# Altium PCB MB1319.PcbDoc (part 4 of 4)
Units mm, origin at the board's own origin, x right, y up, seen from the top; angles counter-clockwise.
Board outline 70 x 82.5 mm, 2 copper layers (Top Layer, Bottom Layer), stack 1.571 mm thick; 252 components, 179 nets, 814 pads, 1000 vias.

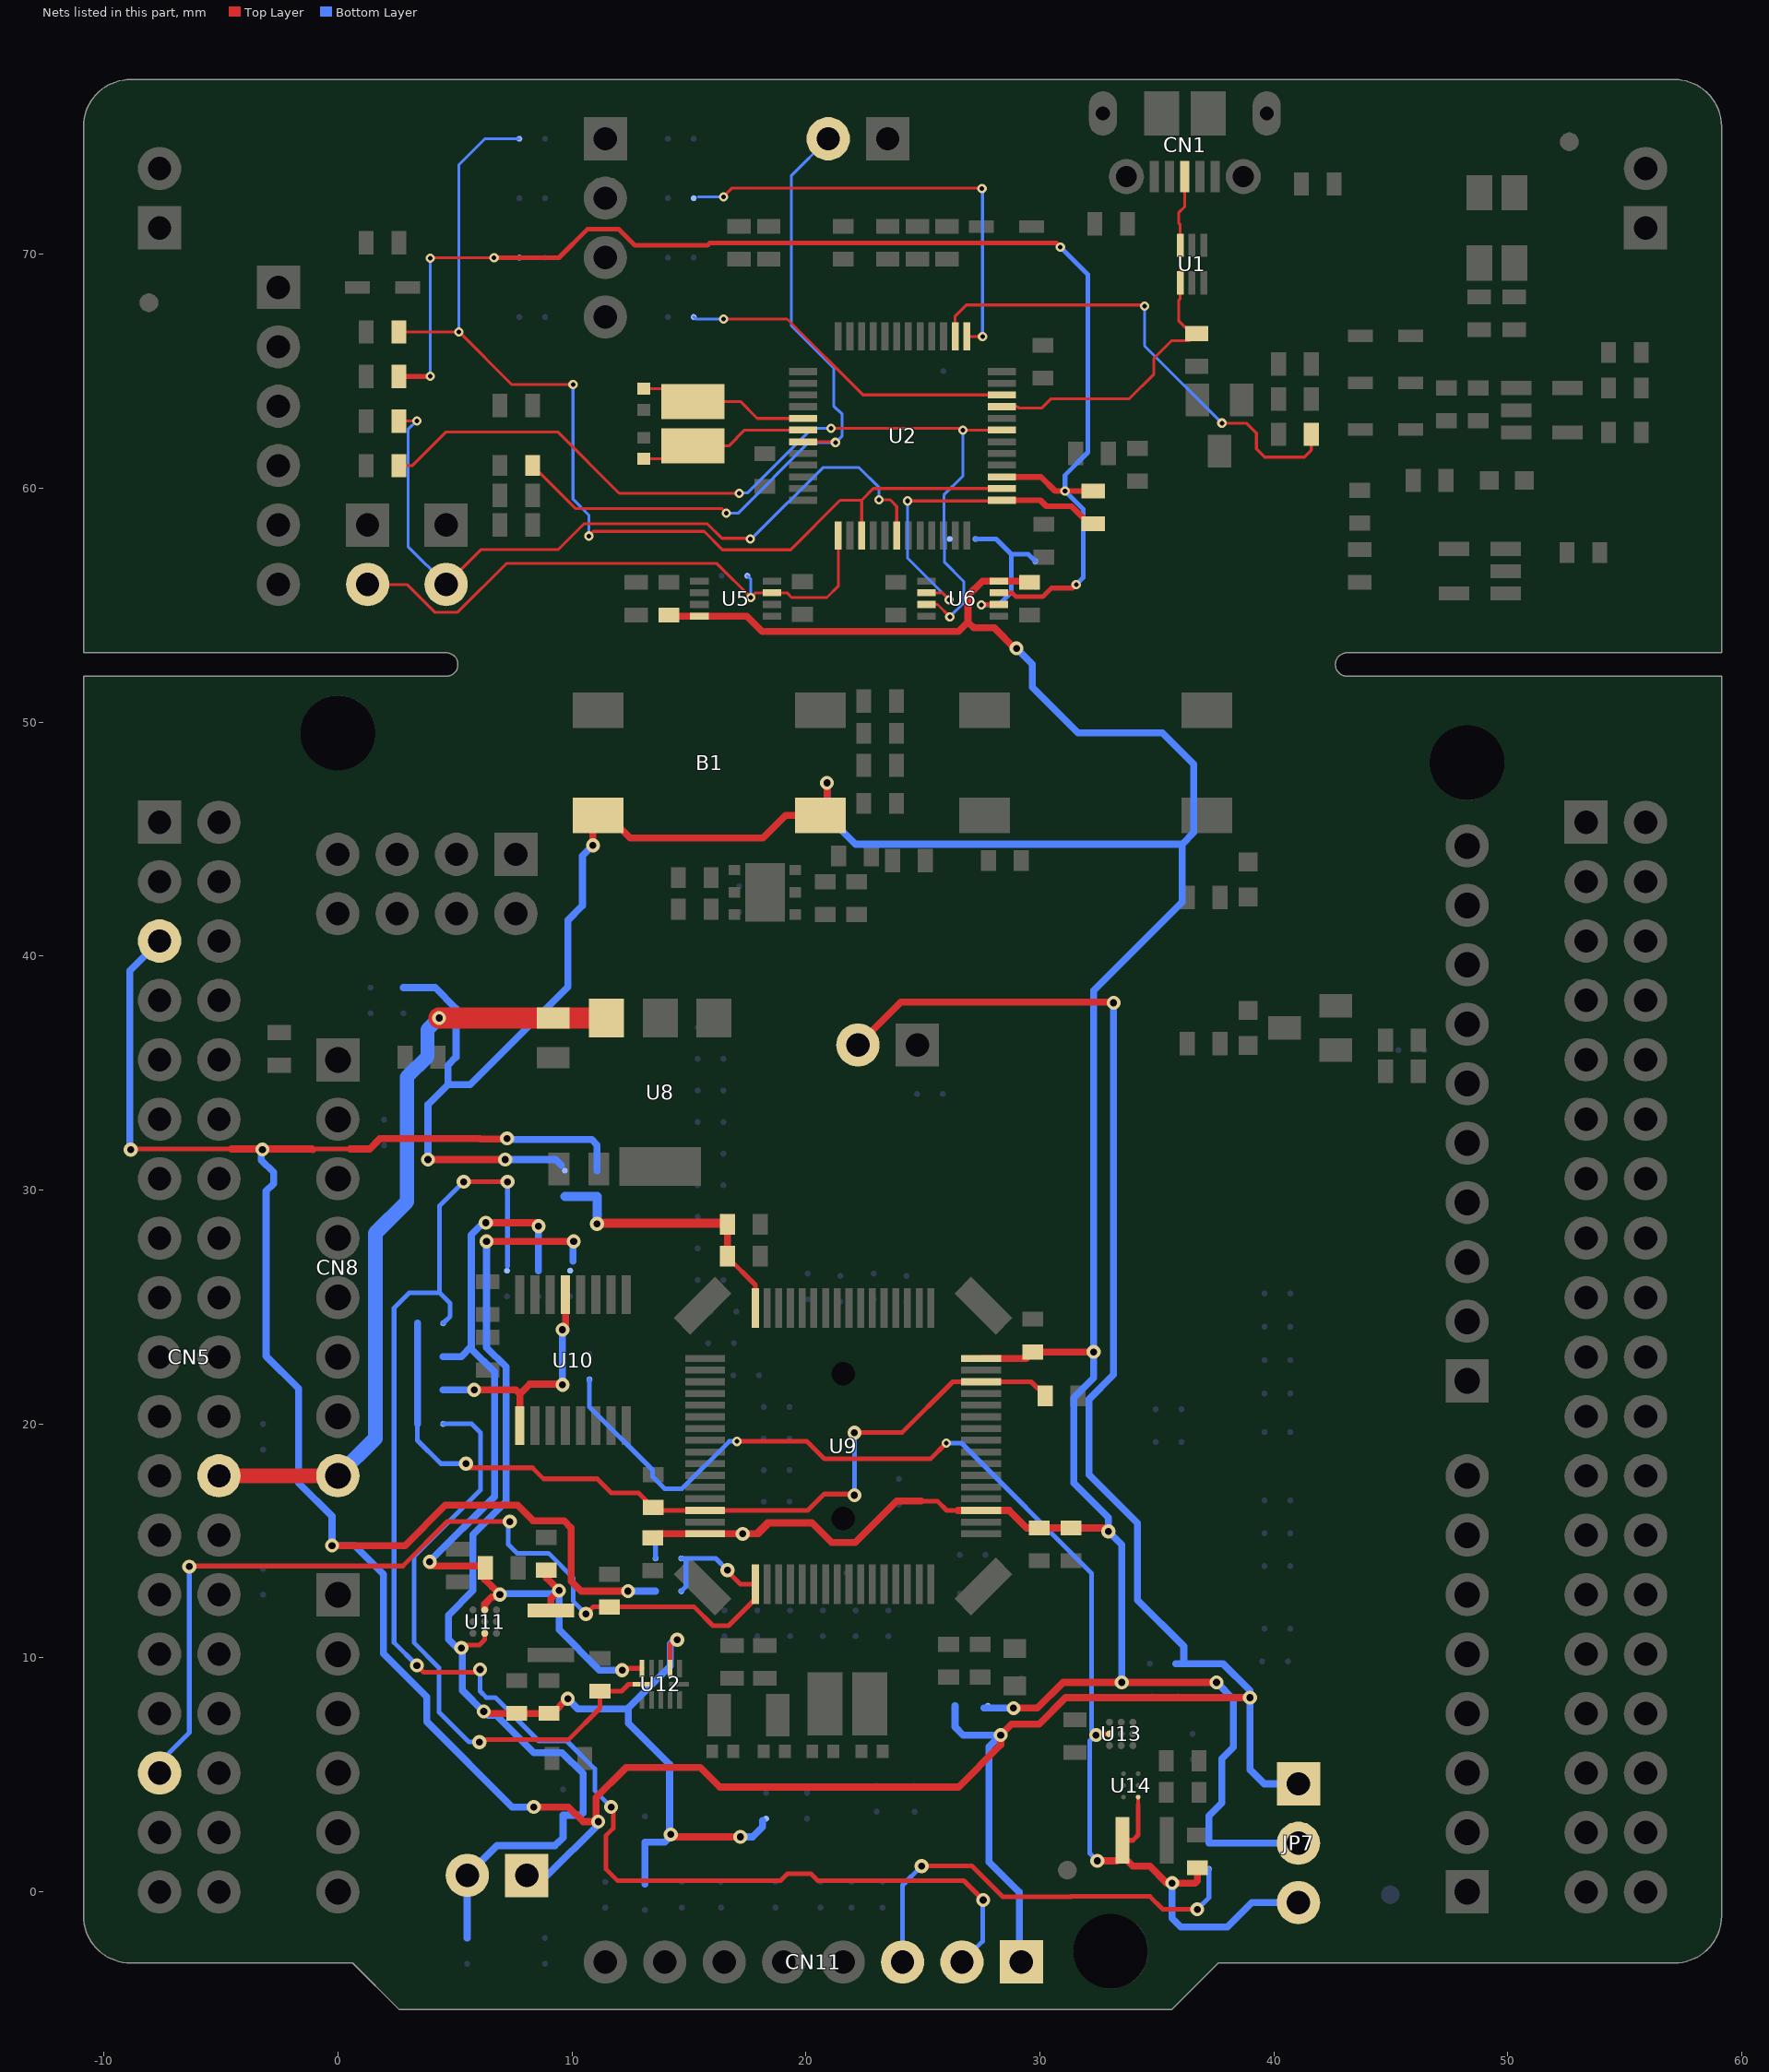
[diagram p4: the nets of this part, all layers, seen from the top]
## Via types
v1: diameter 0.4, hole 0.2, Top Layer to Bottom Layer, tented both sides, 802 vias
v2: diameter 0.6, hole 0.3, Top Layer to Bottom Layer, tented both sides, 198 vias

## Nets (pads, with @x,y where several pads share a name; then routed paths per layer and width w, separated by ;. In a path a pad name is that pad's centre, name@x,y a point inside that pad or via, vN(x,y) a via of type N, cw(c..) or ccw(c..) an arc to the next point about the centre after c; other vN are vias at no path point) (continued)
STLINK_USB_D_P: CN1.3 R12.2 U1.3 U1.4 U2.33 | length 17.4
  Top Layer w0.12: U2.33@28.38,63.48 29.04,63.48 29.105,63.415 30.075,63.415 30.48,63.82 33.822,63.82 34.875,64.873 34.875,65.548 35.622,66.295 36.395,66.295 R12.2@36.7,66.6 36.475,66.6 35.94,67.135 35.94,68.04 36,68.1 U1.4@36,68.77 U1.3@36,70.38 36,71.258 35.94,71.318 35.94,71.782 36.195,72.037 CN1.3@36.195,73.31
STLK_OSC_IN: C7.1 U2.5 X1.2 | length 7.3
  Top Layer w0.127: C7.1@13.075,64.25 14.625,64.25 X1.2@15.175,63.7 17.2,63.7 17.92,62.98 U2.5@19.88,62.98
STLK_OSC_OUT: C9.1 U2.6 X1.1 | length 7.3
  Top Layer w0.127: C9.1@13.075,61.25 14.625,61.25 X1.1@15.175,61.8 16.7,61.8 17.38,62.48 U2.6@19.88,62.48
STLK_RST: C12.2 JP1.2 U2.7 | length 31.2
  Top Layer w0.127: C12.2@8.32,60.96 10.152,59.128 16.397,59.128 v1(16.6,58.925) ; U2.7@19.967,62.067 U2.7@19.88,61.98 21.233,61.98 v1(21.263,61.95)
  Bottom Layer w0.127: v1(16.6,58.925) 17.1,58.925 20.125,61.95 v1(21.263,61.95) 21.55,62.237 21.55,63.153 21.187,63.517 21.187,65.139 19.375,66.95 19.375,73.35 JP1.2@20.955,74.93
STLK_RX: CN4.2 SB12.1 U2.13 U5.3 | length 25.6
  Top Layer w0.12: CN4.2@1.27,55.88 2.949,55.88 4.134,54.695 5.116,54.695 7.196,56.775 16.2,56.775 v1(17.65,55.325) 17.85,55.525 U5.3@18.55,55.525 19.192,55.525 19.392,55.325 20.9,55.325 21.38,55.805 U2.13@21.38,57.98
  Bottom Layer w0.12: SB12.1@17.5,56.25 17.65,56.1 v1(17.65,55.325)
STM_JTCK: SB3.2 U2.37 | length 19.3
  Top Layer w0.127: v1(16.475,72.45) 16.85,72.825 27.5,72.825 v1(27.525,72.8) ; U2.37@26.88,66.48 27.545,66.48 v1(27.55,66.475)
  Bottom Layer w0.127: 15.4,72.45 v1(16.475,72.45) ; v1(27.525,72.8) 27.55,72.775 v1(27.55,66.475)
STM_JTMS: SB7.2 U2.34 | length 14.6
  Top Layer w0.127: v1(16.475,67.225) 19.2,67.225 22.445,63.98 U2.34@28.38,63.98
  Bottom Layer w0.127: SB7.2@15.205,67.31 15.29,67.225 v1(16.475,67.225)
SWO_MCU: SB10.2 SB11.1 U6.6 | length 6.8
  Top Layer w0.2: v1(27.5,55) 27.5,55.025 U6.6@28.25,55.025
  Bottom Layer w0.2: SB10.2@27.25,57.825 28.125,57.825 28.775,57.175 ; v1(27.5,55) 28.225,55 28.775,55.55 28.775,57.175 ; SB11.1@29.8,56.875 29.5,57.175 28.775,57.175
T_JTCK: R11.2 SB2.1 U2.15 U2.26 | length 46
  Top Layer w0.127: R11.2@2.605,66.675 v1(5.175,66.675) 7.425,64.425 v1(10.05,64.425) ; v1(10.725,57.95) 10.922,58.147 15.653,58.147 16.436,57.364 19.349,57.364 21.465,59.48 22.38,59.48 ; U2.15@22.38,57.98 22.38,59.48 ; U2.26@28.38,59.98 22.88,59.98 22.38,59.48
  Bottom Layer w0.127: v1(5.175,66.675) 5.175,73.825 6.28,74.93 SB2.1@7.755,74.93 ; v1(10.05,64.425) 10.05,59.525 10.725,58.85 v1(10.725,57.95)
T_JTMS: R14.2 R23.2 SB6.1 U2.27 U6.7 | length 58.8
  Top Layer w0.127: v1(3.95,69.825) 3.975,69.85 v1(6.675,69.85) ; U2.27@28.375,60.475 U2.27@28.38,60.48
  Top Layer w0.2: R14.2@2.605,64.77 3.945,64.77 v1(3.95,64.775) ; v1(6.675,69.85) 9.45,69.85 10.675,71.075 11.993,71.075 12.693,70.375 15.799,70.375 15.899,70.475 30.7,70.475 v1(30.875,70.3) ; U6.7@28.25,55.525 28.811,55.525 28.981,55.355 30.119,55.355 30.489,55.725 31.4,55.725 v1(31.55,55.875)
  Top Layer w0.25: U2.27@28.38,60.48 30.045,60.48 30.65,59.875 v1(31.075,59.875) R23.2@32.275,59.875
  Bottom Layer w0.127: v1(3.95,64.775) v1(3.95,69.825) ; v1(6.675,69.85) SB6.1@7.755,69.85
  Bottom Layer w0.2: v1(30.875,70.3) 32.05,69.125 32.05,61.525 31.075,60.55 v1(31.075,59.875) 31.85,59.1 31.85,56.175 v1(31.55,55.875)
T_NRST: JP4.2 R17.2 U2.18 | length 32.7
  Top Layer w0.127: R17.2@2.605,62.865 3.365,62.865 v1(3.375,62.875) ; JP4.2@4.625,55.88 6.12,57.375 9.425,57.375 10.524,58.474 15.789,58.474 16.409,57.854 17.6,57.854 v1(17.626,57.828) ; v1(23.125,59.5) 23.6,59.5 23.88,59.22 U2.18@23.88,57.98
  Bottom Layer w0.127: v1(3.375,62.875) 3,62.5 3,57.505 JP4.2@4.625,55.88 ; v1(17.626,57.828) 17.626,57.901 17.65,57.925 17.772,57.925 20.722,60.875 22.275,60.875 23.125,60.025 v1(23.125,59.5)
T_SWDIO_IN: R23.1 U2.25 U6.2 | length 14.4
  Top Layer w0.12: v1(24.35,59.45) 28.35,59.45 U2.25@28.38,59.48 ; U6.2@25.15,55.525 25.825,55.525 v1(26.125,55.225)
  Top Layer w0.25: U2.25@28.38,59.48 30.02,59.48 30.275,59.225 31.35,59.225 32.1,58.475 R23.1@32.275,58.475
  Bottom Layer w0.12: v1(24.35,59.45) 24.35,57 v1(26.125,55.225)
T_SWO: R20.2 SB10.1 U2.31 U6.3 | length 38.8
  Top Layer w0.127: R20.2@2.605,60.96 3.185,60.96 4.625,62.4 9.4,62.4 12.025,59.775 v1(17.15,59.775) ; v1(21.075,62.55) 26.635,62.55 v1(26.705,62.48) U2.31@28.38,62.48 ; U6.3@25.15,55.025 25.625,55.025 v1(26.15,54.5)
  Bottom Layer w0.127: v1(17.15,59.775) 17.175,59.8 17.513,59.8 20.263,62.55 v1(21.075,62.55) ; v1(26.15,54.5) 26.75,55.1 26.75,56 25.925,56.825 25.925,57.825 25.9,57.85 25.9,59.7 26.705,60.505 v1(26.705,62.48)
USB_RENUMN: R18.2 U2.38 | length 21.2
  Top Layer w0.127: U2.38@26.38,66.48 26.38,67.355 26.85,67.825 34.425,67.825 v1(34.475,67.775) ; v1(37.777,62.778) 37.78,62.775 38.825,62.775 39.25,62.35 39.25,61.675 39.6,61.325 41.3,61.325 41.6,61.625 R18.2@41.6,62.3
  Bottom Layer w0.127: v1(34.475,67.775) 34.475,66.08 v1(37.777,62.778)
VBAT: C39.1 CN5.33 SB61.1 SB65.1 U9.1 | length 44.2
  Top Layer w0.2: v2(-6.35,13.9) -6.325,13.925 1.524,13.925 2.775,13.925 4.676,15.826 v2@7.349,15.826 ; v2(10.6,11.875) 10.9,12.175 C39.1@11.6,12.175 15.225,12.175 16.025,11.375 16.7,11.375 17.84,12.515 U9.1@17.84,13.15 17.2,13.15 16.65,13.7 v2(16.65,13.75)
  Bottom Layer w0.2: CN5.33@-7.62,5.08 -7.62,5.53 -6.35,6.8 ; -6.35,7.075 -6.35,6.8 ; v2(-6.35,13.9) -6.35,6.8 ; v2(7.35,15.825) 7.275,15.75 7.275,15.374 7.275,14.85 7.65,14.475 9,14.475 10.05,13.425 10.05,12.425 v2(10.6,11.875) ; SB65.1@14.675,12.85 14.875,13.05 14.875,14.25 ; SB61.1@14.675,14.25 14.875,14.25 ; v2(16.65,13.75) 16.15,14.25 14.875,14.25
VDD: CN5.5 CN11.1 JP6.2 JP7.1 JP8.1 SB24.1 SB65.2 SB76.1 SB77.1 | length 187.1
  Top Layer w0.2: v2(-8.85,31.725) -8.825,31.75 -4.547,31.75 ; -1.2,31.75 -1.1,31.75 0.533,31.75
  Top Layer w0.3: -4.547,31.75 v2@-3.25,31.75 ; v2(-3.225,31.727) -3.227,31.725 -3.227,31.727 v2@-3.25,31.75 ; -1.2,31.75 v2@-3.25,31.75 ; -1.1,31.75 -1.075,31.725 ; v2(-0.25,14.8) 2.875,14.8 4.595,16.52 7.674,16.52 8.344,15.85 9.675,15.85 9.975,15.55 9.975,13.275 10.4,12.85 v2(12.4,12.85) ; 0.533,31.75 1.35,31.75 1.8,32.2 6.056,32.2 6.081,32.175 7.2,32.175 v2(7.225,32.2) ; v2(8.375,3.625) 9.85,3.625 10.475,3 v2(11.125,3) 11.026,3.099 11.026,4.026 12.224,5.224 12.32,5.32 15.48,5.32 15.525,5.275 16.325,4.475 26.525,4.475 28.325,6.275 v2(28.325,6.7) 28.788,7.163 29.963,7.163 31.1,8.3 v2(38.975,8.3) ; JP6.2@22.225,36.195 24.055,38.025 33.125,38.025 v2(33.15,38)
  Bottom Layer w0.3: v2(-8.85,31.725) -8.895,31.77 -8.895,39.365 CN5.5@-7.62,40.64 ; v2(-3.225,31.727) -3.252,31.727 -3.275,31.75 -3.275,31.275 -2.75,30.75 -2.75,30.272 -3.07,29.952 -3.07,22.902 -1.68,21.512 -1.68,17.48 -0.25,16.05 v2(-0.25,14.8) ; v2@-0.358,14.8 v2(-0.25,14.8) ; v2(7.225,32.2) 7.275,32.15 10.85,32.15 11.075,31.925 SB24.1@11.075,30.825 ; JP8.1@8.07,0.7 8.95,0.7 11.125,2.875 v2(11.125,3) v2@11.025,3.1 ; v2(8.375,3.625) 7.45,3.625 3.8,7.275 3.8,8.325 1.95,10.175 1.95,13.575 0.725,14.8 v2(-0.25,14.8) ; v2(12.4,12.85) SB65.2@13.575,12.85 ; SB77.1@26.375,7.95 26.375,7.05 26.725,6.7 v2(28.325,6.7) 27.825,6.2 27.825,1.282 29.125,-0.018 CN11.1@29.125,-3 ; v2(33.15,38) 33.15,22.1 32.1,21.05 32.1,17.825 34.175,15.75 34.175,12.475 36.15,10.5 36.15,9.75 ; SB76.1@35.8,9.75 36.15,9.75 ; 38.975,5.775 38.975,5.225 ; JP7.1@41.05,4.615 39.585,4.615 38.975,5.225 ; 36.15,9.75 37.825,9.75 38.975,8.6 v2(38.975,8.3) 38.975,5.225
VDD_1V2: C33.2 C34.2 SB39.2 SB43.2 SB46.2 SB51.2 U9.30 U9.62 | length 37.2
  Top Layer w0.2: v2(5.475,18.3) 5.65,18.125 8.315,18.125 8.79,17.65 11.082,17.65 11.682,17.05 12.85,17.05 C34.2@13.475,16.425 13.6,16.3 U9.62@15.69,16.3 20.075,16.3 20.775,17 22.05,17 22.076,16.974 v2(22.076,16.951) ; v2(22.076,19.624) 24.099,19.624 26.275,21.8 U9.30@27.49,21.8 29.625,21.8 C33.2@30.225,21.2
  Bottom Layer w0.2: SB51.2@3.4,20 3.4,19.3 4.4,18.3 v2(5.475,18.3) ; v2(22.076,16.951) v2(22.076,19.624)
  Bottom Layer w0.3: SB51.2@3.4,20 SB46.2@3.4,21.45 SB43.2@3.4,22.875 SB39.2@3.4,24.3
VDD_1V2_SW: SB46.1 U10.1 U10.13 | length 10.7
  Top Layer w0.3: v2(5.825,21.45) 7.603,21.45 7.775,21.278 ; U10.1@7.775,19.925 7.775,21.278 ; v2(9.6,24.025) 9.725,24.15 U10.13@9.725,25.525 ; v2@9.601,21.675 9.626,21.7 8.197,21.7 7.775,21.278
  Bottom Layer w0.3: SB46.1@4.5,21.45 v2(5.825,21.45) ; v2(9.6,21.675) v2(9.6,24.025)
VDD_IN_SMPS: C43.2 C44.2 JP8.2 SB29.1 SB83.1 SB85.1 SB86.1 SB94.1 SB96.1 U11.A2 U12.2 | length 72.1
  Top Layer w0.12: 14.2,10.575 14.4,10.775 v2(14.5,10.775)
  Top Layer w0.2: v2(5.275,10.425) 5.4,10.55 6.05,10.55 6.275,10.775 U11.A2@6.275,11.05 ; U12.2@14.2,9.55 14.2,10.575
  Top Layer w0.3: v2@5.175,10.425 v2(5.275,10.425) ; v2(6.233,7.708) 6.316,7.625 C43.2@7.65,7.625 C44.2@9.025,7.625 9.175,7.625 9.8,8.25 v2(9.825,8.25) ; v2(6.35,27.8) v2(10.075,27.8) ; v2(14.225,2.45) 14.325,2.35 v2(17.2,2.35)
  Bottom Layer w0.12: 14.151,10.576 14.35,10.775 v2(14.5,10.775)
  Bottom Layer w0.2: 18.15,2.925 18.2,2.925
  Bottom Layer w0.3: v2(5.275,10.425) 5.095,10.425 4.772,10.747 4.772,10.751 4.725,10.799 4.725,11.825 5.775,12.875 5.775,15.27 7.19,16.685 7.19,22.432 6.35,23.272 ; v2@5.3,10.225 5.325,10.2 5.325,8.616 v2(6.233,7.708) 6.25,7.725 6.425,7.55 6.773,7.55 7.984,6.339 7.984,6.337 8.371,5.95 9.575,5.95 10.475,5.05 10.475,3.375 10.375,3.275 SB83.1@9.625,3.275 9.625,2.325 9.275,1.975 ; SB96.1@5.525,-1.975 5.525,0.695 JP8.2@5.53,0.7 6.805,1.975 9.275,1.975 ; 6.35,24.725 6.35,23.272 ; v2(6.35,27.8) 6.35,23.272 ; 9.413,2.113 9.275,1.975 ; v2(9.825,8.25) 10.255,7.82 12.366,7.82 12.411,7.865 ; 10.05,26.95 10.05,27.775 v2(10.075,27.8) ; SB94.1@13.125,0.325 SB86.1@13.125,2.125 13.975,2.125 14.225,2.375 v2(14.225,2.45) 14.175,2.5 14.175,5.447 12.411,7.211 12.411,7.865 ; v2(14.5,10.775) 14.375,10.775 14.201,10.601 14.201,9.655 12.411,7.865 ; v2(17.2,2.35) 17.725,2.35 18.15,2.775 18.15,2.925 18.15,3.05
VDD_MCU: B1.1 B1.2 C17.1 C19.1 C32.2 C35.2 C36.2 C38.2 JP7.2 SB14.2 SB25.1 SB61.2 SB78.1 SB87.2 U5.8 U6.8 U9.19 U9.32 U9.64 | length 187.6
  Top Layer w0.2: C38.2@13.45,15.125 C38.2@13.625,15.3 ; 17.825,15.3 18.35,15.825 20.205,15.825 20.26,15.77 ; 24.925,16.7 25.618,16.7 26.018,16.3 26.503,16.3
  Top Layer w0.3: v2(3.85,31.3) v2(7.15,31.3) ; B1.2@10.525,45.675 10.79,45.675 B1.2@11.125,46.01 B1.2@11.165,46.01 ; v2(10.9,44.725) 10.9,45.745 B1.2@11.165,46.01 ; C38.2@13.325,15.15 13.4,15.075 C38.2@13.45,15.125 ; C38.2@13.625,15.3 U9.64@15.69,15.3 v2(17.3,15.3) 17.825,15.3 17.97,15.3 18.44,15.77 20.26,15.77 21.105,14.925 22.1,14.925 23.875,16.7 24.925,16.7 ; C17.1@14.15,54.575 14.2,54.525 U5.8@15.45,54.525 17.475,54.525 18.125,53.875 26.525,53.875 26.925,54.275 ; v2(20.899,47.399) 20.899,46.284 B1.1@20.625,46.01 19.125,46.01 18.165,45.05 12.5,45.05 11.525,46.025 11.15,46.025 B1.2@11.165,46.01 ; 26.503,16.3 U9.19@27.49,16.3 28.692,16.3 29.442,15.55 C35.2@29.975,15.55 C36.2@31.325,15.55 32.775,15.55 v2(32.925,15.4) ; U9.32@27.49,22.8 29.425,22.8 C32.2@29.7,23.075 v2(32.3,23.075) ; v2(28.875,7.85) 29.9,7.85 31,8.95 v2(33.5,8.95) v2(37.55,8.95) ; v2(29,53.15) 28.925,53.15 28.05,54.025 27.175,54.025 26.925,54.275 ; C19.1@29.55,55.975 29.5,56.025 U6.8@28.25,56.025 27.55,56.025 26.925,55.4 26.925,54.275
  Bottom Layer w0.2: SB61.2@13.575,14.25 13.575,15.05 13.825,15.3 v2(17.3,15.3)
  Bottom Layer w0.3: SB14.2@2.8,38.65 4.15,38.65 5.05,37.75 5.05,35.675 4.7,35.325 4.7,34.5 ; v2(3.85,31.3) 3.85,33.65 4.7,34.5 ; v2(7.15,31.3) 9.3,31.3 9.55,31.05 ; v2(10.9,44.725) 10.45,44.275 10.45,42.151 9.825,41.526 9.825,38.675 5.65,34.5 4.7,34.5 ; v2(20.899,47.399) 20.899,46.01 22.132,44.777 36.075,44.777 ; 27.6,7.85 v2(28.875,7.85) ; v2(29,53.15) 29.68,52.47 29.68,51.494 31.634,49.54 35.235,49.54 36.575,48.2 36.575,45.275 36.075,44.775 36.075,42.3 32.3,38.525 v2(32.3,23.075) 32.3,21.975 31.45,21.125 31.45,17.475 32.925,16 v2(32.925,15.4) 33.5,14.825 v2(33.5,8.95) ; v2(37.55,8.95) 38.275,8.225 38.275,6.185 37.775,5.685 37.775,3.8 37.225,3.25 SB87.2@37.225,2.075 JP7.2@41.05,2.075
VDD_SMPS_1V2: C37.2 L1.2 R40.2 SB30.1 SB43.1 U11.C2 U12.5 | length 38.5
  Top Layer w0.2: v2@12.15,9.55 v2(12.15,9.475) 12.225,9.55 U12.5@13,9.55
  Top Layer w0.3: v2(3.925,14.1) 4.105,13.92 6.23,13.92 R40.2@6.3,13.85 6.3,13.326 ; R40.2@6.25,13.575 6.25,13.376 6.3,13.326 ; U11.C2@6.275,12.05 6.275,12.3 6.575,12.6 6.925,12.6 v2(6.925,12.701) 6.3,13.326 ; v2(6.325,28.6) 8.427,28.6 v2(8.575,28.451) ; 6.575,13.05 6.3,13.326 ; C37.2@8.9,13.75 8.9,13.425 v2(9.45,12.875) 9.1,12.525 L1.2@9.1,12.025
  Bottom Layer w0.3: v2(3.925,14.1) 3.925,14.127 6.69,16.892 6.69,22.225 5.7,23.215 5.7,23.3 ; SB43.1@4.5,22.875 5.275,22.875 5.7,23.3 ; v2(6.325,28.6) 6.231,28.6 5.7,28.069 5.7,23.3 ; v2(6.925,12.701) 6.925,12.625 7.051,12.75 9.325,12.75 v2(9.45,12.875) 9.45,11.2 11.175,9.475 v2(12.15,9.475) ; SB30.1@8.575,26.55 v2(8.575,28.451)
VDD_SMPS_1V8: C51.2 JP7.3 L3.2 SB42.1 U13.C2 U14.E3 | length 57.3
  Top Layer w0.15: 34.2,3.7 U14.E3@34.2,4.05
  Top Layer w0.2: v1(17.05,19.25) 20.05,19.25 20.8,18.5 25.325,18.5 v1(26,19.175) ; v2(32.402,6.7) 32.402,6.723 32.375,6.75 U13.C2@32.975,6.75 ; L3.2@33.525,2.2 33.975,2.2 34.2,2.425 34.2,3.7
  Top Layer w0.3: v2(32.45,1.325) 33.3,1.325 L3.2@33.525,1.55 ; L3.2@33.525,2.2 L3.2@33.525,1.55 ; v2@35.652,0.352 v2(35.652,0.375) ; C51.2@36.725,1.025 36.725,0.475 36.625,0.375 v2(35.652,0.375) ; L3.2@33.525,1.55 33.975,1.1 34.696,1.1 35.421,0.375 v2(35.652,0.375)
  Bottom Layer w0.2: SB42.1@10.75,21.9 10.75,20.726 13.445,18.031 13.445,17.75 13.969,17.226 14.701,17.226 16.725,19.25 v1(17.05,19.25) ; v1(26,19.175) 26.65,19.175 32.2,13.625 32.2,6.902 v2@32.388,6.713 ; v2@32.368,6.7 v2@32.375,6.7 ; v2@32.402,6.727 v2@32.388,6.713 ; v2(32.45,1.325) 32.125,1.65 32.125,6.45 v2@32.375,6.7 ; v2@32.375,6.7 v2@32.388,6.713 ; v2@32.375,6.7 v2(32.402,6.7) v2@32.388,6.713
  Bottom Layer w0.3: v2(35.652,0.375) 35.65,0.373 35.65,-1.125 36.025,-1.5 38.015,-1.5 39.05,-0.465 JP7.3@41.05,-0.465
VDDUSB: C30.1 C31.2 SB24.2 SB25.2 U9.48 | length 12.5
  Top Layer w0.2: C31.2@16.65,27.175 16.65,27.125 17.84,25.935 U9.48@17.84,24.95
  Top Layer w0.3: C31.2@16.65,27.175 C30.1@16.65,28.525
  Top Layer w0.4: v2(11.075,28.55) 11.075,28.575 16.45,28.575 16.6,28.725 16.65,28.725 C30.1@16.65,28.525
  Bottom Layer w0.4: SB25.2@9.7,29.725 SB24.2@11.075,29.725 v2(11.075,28.55)
VIN: C28.2 CN5.24 CN8.8 U8.3 | length 33.6
  Top Layer w0.635: CN5.24@-5.08,17.78 CN8.8@0,17.78
  Top Layer w0.9: v2(4.325,37.35) C28.2@9.2,37.35 U8.3@11.475,37.35
  Bottom Layer w0.6: 2.95,29.5 2.95,34.825 3.825,35.7 3.825,36.85 v2(4.325,37.35)
  Bottom Layer w0.635: CN8.8@0,17.78 1.603,19.383 1.603,28.153 2.95,29.5
VOUT2: C42.2 SB51.1 U12.6 | length 26
  Top Layer w0.2: v2(6.05,6.4) 6.15,6.5 9.85,6.5 11.2,7.85 C42.2@11.2,8.575 12.125,8.575 12.425,8.875 U12.6@13.025,8.875
  Bottom Layer w0.2: SB51.1@4.5,20 5.725,20 6.1,19.625 6.1,17.175 3.25,14.325 3.25,10.65 4.325,9.575 4.325,7.675 5.6,6.4 v2(6.05,6.4)
VOUTCORE: CN11.2 SB31.1 SB39.1 | length 65.5
  Top Layer w0.2: v2(3.375,9.675) 3.665,9.385 5.96,9.385 v2(6.075,9.5) ; v2(5.375,30.35) v2(7.25,30.35) ; v2(11.676,3.625) 11.676,3.574 11.764,3.486 11.764,2.714 11.45,2.4 11.45,0.975 11.955,0.47 18.909,0.47 19.204,0.765 20.222,0.765 20.512,0.475 26.75,0.475 v2(27.575,-0.35)
  Bottom Layer w0.2: v2(3.375,9.675) 2.4,10.651 2.4,24.95 3.05,25.6 4.35,25.6 ; SB39.1@4.5,24.3 4.8,24.6 4.8,25.15 4.35,25.6 ; v2(5.375,30.35) 4.35,29.325 4.35,25.6 ; v2(6.075,9.5) 6.075,8.573 6.34,8.308 6.722,8.308 ; 7.05,7.98 6.722,8.308 ; 7.25,26.75 v2(7.25,30.35) ; CN11.2@26.67,-3 27.55,-2.12 27.55,-0.375 v2(27.575,-0.35) ; 6.722,8.308 8.58,6.45 9.782,6.45 10.975,5.257 10.975,4.326 v2@11.6,3.701 ; v2@11.6,3.701 v2(11.676,3.625) 11.6,3.625 v2@11.6,3.701
VOUTVDD: CN11.3 SB87.1 | length 18.9
  Top Layer w0.2: v2(24.95,1.1) 27.1,1.1 28.409,-0.209 31.312,-0.209 31.32,-0.2 34.703,-0.2 35.253,-0.75 v2(36.725,-0.75)
  Bottom Layer w0.2: CN11.3@24.13,-3 24.125,-2.995 24.125,0.275 v2(24.95,1.1) ; v2(36.725,-0.75) 37.225,-0.25 SB87.1@37.225,0.975
pads on no net: CN5.9 CN5.10 CN5.11 CN5.21 CN5.26 MIRE-1.1 MIRE-2.1 MIRE-3.1 MIRE-4.1 MIRE-5.1 MIRE-6.1 U2.4 U2.11 U2.14 U2.16 U2.17 U2.19 U2.21 U2.22 U2.40 U2.41 U2.42 U2.43 U2.45 U2.46 U5.2 U7.3 U7.5 U9.0 U10.3 U10.5 U10.9 U10.10 U10.11 U10.15 U13.C1 U14.E1

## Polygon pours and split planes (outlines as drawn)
5V_VIN on Top Layer "5V_VIN_L01_P000" (solid, remove dead copper, pour order 0): 12.725,38.175 12.5,38.4 5.175,38.4 4.45,39.125 4.45,39.975 4.85,40.375 16.975,40.375 17.37,39.98 17.37,38.82 17.2,38.65 16.979,38.433 16.931,38.481 15.356,38.481 15.075,38.2 15.075,36.475 15.275,36.275 18.175,36.275 19.025,35.425 19.025,31.525 17.525,30.025 10.55,30.025 10.275,30.3 10.275,35.825 10.575,36.125 12.55,36.125 12.725,36.3
GND on Top Layer "GND_L01_P002" (solid, remove dead copper, pour order 2): -11,78 -11,-2 -7,-6 56,-6 60,-2 60,76 58,78
GND on Bottom Layer "GND_L02_P004" (solid, remove dead copper, pour order 4): -11,78 -11,-2 -7,-6 36,-6 38,-4 58,-4 60,-2 60,77 59,78

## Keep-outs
Keep-Out Layer:
  lines w0.127: 37.63,-3.04 35.63,-5.04 2.63,-5.04 0.63,-3.04 -8.87,-3.04 cw(c-8.87,-1.04) -10.87,-1.04 -10.87,51.96 4.63,51.96 ccw(c4.63,52.46) 4.63,52.96 -10.87,52.96 -10.87,75.46 cw(c-8.87,75.46) -8.87,77.46 57.13,77.46 cw(c57.13,75.46) 59.13,75.46 ; 37.63,-3.04 37.63,-3.04 ; 37.63,-3.04 57.13,-3.04 ccw(c57.13,-1.04) 59.13,-1.04 59.13,51.96 43.13,51.96 cw(c43.13,52.46) 43.13,52.96 59.13,52.96 59.13,75.46 ; 59.13,75.46 59.13,75.46 ; 8.13,51.96 cw(c8.13,52.46) 8.13,52.96 27.13,52.96 cw(c27.13,52.46) 27.13,51.96 8.13,51.96 ; 31.75,51.96 cw(c31.75,52.46) 31.75,52.96 39.08,52.96 cw(c39.08,52.46) 39.08,51.96 31.75,51.96
  text "BOARD OUTLINE" at 11.7,-25.925 h2

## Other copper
Top Layer:
  pour cut-out: 41.618,26.288 41.625,26.281 41.625,23.875 41.35,23.6 41.35,21.325 42.9,19.775 45.875,19.775 46.05,19.95 45.775,20.225 45.775,21.1 48.025,23.35 48.025,25.825 47.55,26.3
  pour cut-out: 14.25,44.75 14.275,44.725 14.275,43.655 13.535,42.915 13.575,42.875 13.575,41.675 12.7,40.8 8.8,40.8 8.08,41.52 8.175,41.615 8.175,44.75
  pour cut-out: -9.5,57.25 -9.5,54.25 -5.75,54.25 -5.75,57.25
  text "1" at -9,55 h1.5
  text "1" at 18.55,-20.325 h2
  text "PRIMARY SIDE" at 4.05,-25.825 h2
Bottom Layer:
  pour cut-out: -9.5,57.25 -9.5,54.25 -5.75,54.25 -5.75,57.25
  text "2" at -6.5,55 h1.5
  text "2" at 18.55,-20.325 h2
  text "SECONDARY SIDE" at 4.05,-25.825 h2
Multi-Layer:
  circle w0.2: c-19.926,85.064 r1.922
  circle w0.2: c-19.926,85.064 r3.442
  circle w0.2: c68.074,87.064 r1.922
  circle w0.2: c68.074,87.064 r3.442
  circle w0.2: c-23.926,-7.936 r1.922
  circle w0.2: c-23.926,-7.936 r3.442
  lines w0.2: -29.895,-8 -17.893,-8 ; -25.895,85 -13.893,85 ; -23.926,-14.032 -23.926,-2.031 ; -19.926,78.968 -19.926,90.969 ; 62.105,87 74.107,87 ; 68.074,80.968 68.074,92.969

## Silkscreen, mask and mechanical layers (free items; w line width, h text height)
Top Overlay:
  drawing of 1764 lines, arcs and shapes, not listed
  text "USB" at 29.05,75.825 h1
  text "ST_LINK" at 26.45,74.425 h1
  text "STL_NRST" at 19,72.3 h1
  text "GND" at -4.75,71.25 h1 r90
  text "GND" at 54.102,70.866 h1 r90
  text "SWD" at -3.925,70.3 h1
  text "COM" at 52.575,69.65 h1 r90
  text "NUCLEO" at 16.256,68.326 h1 r90
  text "ST-LINK" at 8.382,67.945 h1 r90
  text "8MHz" at 13.775,64.75 h0.8
  text "TX" at -0.2,57.775 h0.8 r90
  text "nRST" at 6.3,55.875 h1.02
  text "RX" at -0.2,55.225 h0.8 r90
  text "E5V" at 3.1,45.95 h1.1 r90
  text "5V_STL" at 8.05,45.95 h1.1 r90
  text "5V_VIN" at 5.475,45.925 h1.1 r90
  text "5V_CHG" at -2.075,45.175 h1.1 r90
  text "SCL/D15" at 40.894,44.196 h1.02
  text "RESET" at 30.4,43.5 h1.2
  text "5V" at 36.175,43.35 h1.2
  text "SDA/D14" at 40.894,41.402 h1.02
  text "5V" at 9.225,41.225 h1.1
  text "B_USER" at 13,39.6 h1 r90
  text "E5V" at -3.5,39.275 h1.02
  text "PWR Input" at 0.175,39.025 h1.2
  text "AVDD" at 42.926,38.862 h1.02
  text "3V3" at 17.25,38.375 h1
  text "IDD" at 22.6,37.85 h1
  text "GND" at -3.556,37.592 h1.02
  text "GND" at 43.85,37.325 h1.02
  text "ARD" at 35.075,37.175 h1.2
  text "RoHS" at 29.775,34.25 h1.6 r90
  text "COMPLIANT" at 31.175,33.85 h0.8 r90
  text "2002/95/EC" at 32.475,33.35 h0.8 r90
  text "SCK/D13" at 40.675,33 h1.02
  text "IOREF" at 1.524,32.512 h1.02
  text "5V_VIN" at 17.5,32.525 h1.2
  text "MISO/D12" at 40.386,31.242 h1.02
  text "www.st.com/stm32nucleo" at 17.1,30.525 h1.2
  text "NRST" at 1.524,29.718 h1.02
  text "PWM/MOSI/D11" at 36.576,28.702 h1.02
  text "MB1319C" at 24.675,28.2 h1.5
  text "VDD_1V2" at 7.75,27.5 h1.02
  text "3V3" at 1.524,27.432 h1.02
  text "PWM/CS/D10" at 37.592,26.162 h1.02
  text "5V" at 1.524,24.638 h1.02
  text "PWM/D9" at 41.148,23.622 h1.02
  text "GND" at 1.524,22.098 h1.02
  text "D8" at 44.958,21.082 h1.02
  text "POWER" at 5.5,20.75 h1.02 r90
  text "GND" at 1.524,19.558 h1.02
  text "VIN" at 1.524,17.018 h1.02
  text "D7" at 44.958,17.018 h1.02
  text "PWM/D6" at 41.148,14.478 h1.02
  text "A0" at 1.524,11.938 h1.02
  text "PWM/D5" at 41.148,11.938 h1.02
  text "8MHz" at 20.4,9.65 h0.8
  text "A1" at 1.524,9.398 h1.02
  text "D4" at 44.958,9.398 h1.02
  text "VDD_MCU" at 32.575,9.15 h1.02
  text "AIN" at 4.572,8.382 h1.02 r90
  text "A2" at 1.524,6.858 h1.02
  text "PWM/D3" at 41.148,6.858 h1.02
  text "1V2" at 6.733,6.708 h1.02 r90
  text "1V2" at 11.125,5.55 h1.02
  text "1V8" at 31.15,4.575 h0.8
  text "A3" at 1.524,4.318 h1.02
  text "D2" at 44.958,4.318 h1.02
  text "32.768KHz" at 14.75,3.475 h0.8
  text "3V3" at 39.025,2.425 h1.02 r90
  text "TX/D1" at 43.05,2.025 h1.02
  text "A4" at 1.524,1.778 h1.02
  text "VDD_IN_SMPS" at 9.75,0.25 h1.02
  text "RX/D0" at 42.625,-0.65 h1.02
  text "1V8" at 39.025,-0.675 h1.02 r90
  text "A5" at 1.524,-0.762 h1.02
  text "SILKSCREEN, (PRIMARY)" at 4.05,-25.825 h2
Bottom Overlay:
  drawing of 2496 lines, arcs and shapes, not listed
  text "3V3" at 19.475,74.65 h1
  text "RoHS" at 1.875,73.775 h1.6
  text "COMPLIANT" at 2.275,72.375 h0.8
  text "SWCLK" at 22.975,71.9 h1
  text "2002/95/EC" at 2.775,71.075 h0.8
  text "GND" at 21.275,69.425 h1
  text "DEFAULT" at 5.15,68.225 h1 r270
  text "RESERVED" at 16.675,67.7 h1 r270
  text "SWDIO" at 22.625,66.8 h1
  text "SN" at 32,64.5 h1.5
  text "CPN" at 35.5,49.425 h1.5
  text "1" at -8.89,45.212 h1
  text "2" at 57.785,45.212 h1
  text "10" at 51.181,44.069 h1.2
  text "3" at -8.89,42.672 h1
  text "4" at 57.785,42.672 h1
  text "www.st.com/stm32nucleo" at 46.125,41.75 h1.5
  text "9" at 50.292,41.529 h1.2
  text "5" at -8.89,40.132 h1
  text "6" at 57.785,40.132 h1
  text "8" at 50.292,38.989 h1.2
  text "7" at -8.89,37.592 h1
  text "8" at 57.785,37.592 h1
  text "7" at 50.292,36.449 h1.2
  text "9" at -8.89,35.052 h1
  text "1" at -1.27,35.052 h1
  text "10" at 58.547,35.052 h1
  text "6" at 50.292,33.909 h1.2
  text "11" at -8.89,32.512 h1
  text "2" at -1.27,32.512 h1
  text "12" at 58.547,32.512 h1
  text "5" at 50.292,31.369 h1.2
  text "13" at -8.89,29.972 h1
  text "3" at -1.27,29.972 h1
  text "14" at 58.547,29.972 h1
  text "4" at 50.292,28.829 h1.2
  text "15" at -8.89,27.432 h1
  text "4" at -1.27,27.432 h1
  text "16" at 58.547,27.432 h1
  text "3" at 50.292,26.289 h1.2
  text "17" at -8.89,24.892 h1
  text "5" at -1.27,24.892 h1
  text "18" at 58.547,24.892 h1
  text "2" at 50.292,23.749 h1.2
  text "19" at -8.89,22.352 h1
  text "6" at -1.27,22.352 h1
  text "20" at 58.674,22.352 h1
  text "1" at 49.911,21.209 h1.2
  text "21" at -8.89,19.812 h1
  text "7" at -1.27,19.812 h1
  text "22" at 58.674,19.812 h1
  text "23" at -8.89,17.272 h1
  text "8" at -1.27,17.272 h1
  text "24" at 58.674,17.272 h1
  text "8" at 50.292,17.145 h1.2
  text "25" at -8.89,14.732 h1
  text "26" at 58.674,14.732 h1
  text "7" at 50.292,14.605 h1.2
  text "27" at -8.89,12.192 h1
  text "1" at -1.27,12.192 h1
  text "28" at 58.674,12.192 h1
  text "6" at 50.292,12.065 h1.2
  text "29" at -8.89,9.652 h1
  text "2" at -1.27,9.652 h1
  text "30" at 58.674,9.652 h1
  text "5" at 50.292,9.525 h1.2
  text "MB1319C" at 12.025,9.475 h1.5
  text "31" at -8.89,7.112 h1
  text "3" at -1.27,7.112 h1
  text "32" at 58.674,7.112 h1
  text "4" at 50.292,6.985 h1.2
  text "33" at -8.89,4.572 h1
  text "4" at -1.27,4.572 h1
  text "34" at 58.674,4.572 h1
  text "3" at 50.292,4.445 h1.2
  text "35" at -8.89,2.032 h1
  text "5" at -1.27,2.032 h1
  text "36" at 58.674,2.032 h1
  text "2" at 50.292,1.905 h1.2
  text "37" at -8.89,-0.508 h1
  text "6" at -1.27,-0.508 h1
  text "38" at 58.674,-0.508 h1
  text "1" at 49.911,-0.635 h1.2
  text "SILKSCREEN, (SECONDARY)" at 44.725,-25.575 h2
Top Paste:
  text "SOLDER PASTE, (PRIMARY)" at 4.05,-25.825 h2
Bottom Paste:
  text "SOLDER PASTE, (SECONDARY)" at 4.05,-25.825 h2
Top Solder:
  rectangle: -9.25,54.5 -6,57
  text "SOLDER MASK, (PRIMARY)" at 4.05,-25.825 h2
Bottom Solder:
  rectangle: -9.25,54.5 -6,57
  text "SOLDER MASK, (SECONDARY)" at 4.05,-25.825 h2
Mechanical 1:
  lines w0.127: 35.63,-5.04 37.63,-3.04 57.13,-3.04 ccw(c57.13,-1.04) 59.13,-1.04 59.13,51.96 43.13,51.96 cw(c43.13,52.46) 43.13,52.96 59.13,52.96 59.13,75.46 ccw(c57.13,75.46) 57.13,77.46 -8.87,77.46 ccw(c-8.87,75.46) -10.87,75.46 -10.87,52.96 4.63,52.96 cw(c4.63,52.46) 4.63,51.96 -10.87,51.96 -10.87,-1.04 ccw(c-8.87,-1.04) -8.87,-3.04 0.5,-3.04 0.63,-3.04 2.63,-5.04 35.63,-5.04 ; 35.63,-5.04 35.63,-5.04 ; 8.13,51.96 cw(c8.13,52.46) 8.13,52.96 27.13,52.96 cw(c27.13,52.46) 27.13,51.96 8.13,51.96 ; 31.75,51.96 cw(c31.75,52.46) 31.75,52.96 39.08,52.96 cw(c39.08,52.46) 39.08,51.96 31.75,51.96
Mechanical 2:
  circle w0.2: c-19.925,85.064 r3.442
  circle w0.2: c-19.925,85.064 r1.922
  circle w0.2: c68.075,87.064 r3.442
  circle w0.2: c68.075,87.064 r1.922
  circle w0.2: c-23.925,-7.936 r3.442
  circle w0.2: c-23.925,-7.936 r1.922
  lines w0.2: -29.894,-8 -17.892,-8 ; -25.894,85 -13.892,85 ; -23.925,-14.032 -23.925,-2.031 ; -19.925,78.968 -19.925,90.969 ; 62.106,87 74.108,87 ; 68.075,80.968 68.075,92.969
Drill Drawing:
  circle w0.11: c78.603,75.111 r0.611
  lines w0.11: 77.992,61.056 78.297,61.056 78.297,60.75 78.908,60.75 78.908,61.056 79.214,61.056 79.214,61.667 78.908,61.667 78.908,61.972 78.297,61.972 78.297,61.667 77.992,61.667 77.992,61.056 ; 77.992,63.5 78.603,63.806 79.214,63.5 78.908,64.111 79.214,64.722 78.603,64.417 77.992,64.722 78.297,64.111 77.992,63.5 ; 77.992,66.25 79.214,66.25 79.214,67.472 77.992,67.472 77.992,66.25 ; 77.992,69.306 78.297,69.306 78.603,69 78.908,69.306 79.214,69.306 78.908,69.611 79.214,69.917 78.908,69.917 78.603,70.222 78.297,69.917 77.992,69.917 78.297,69.611 77.992,69.306 ; 77.992,72.972 79.214,72.972 78.603,71.75 77.992,72.972 ; 77.992,77.25 78.603,77.556 79.214,77.25 78.908,77.861 79.214,78.472 78.603,78.167 77.992,78.472 78.297,77.861 77.992,77.25 ; 77.992,80.306 78.297,80.306 78.297,80 78.908,80 78.908,80.306 79.214,80.306 79.214,80.917 78.908,80.917 78.908,81.222 78.297,81.222 78.297,80.917 77.992,80.917 77.992,80.306 ; 78.236,77.494 78.603,77.678 78.969,77.494 78.786,77.861 78.969,78.228 78.603,78.044 78.236,78.228 78.419,77.861 78.236,77.494 ; 78.236,80.428 78.419,80.428 78.419,80.244 78.786,80.244 78.786,80.428 78.969,80.428 78.969,80.794 78.786,80.794 78.786,80.978 78.419,80.978 78.419,80.794 78.236,80.794 78.236,80.428
  lines w0.127: 37.63,-3.04 35.63,-5.04 2.63,-5.04 0.63,-3.04 -8.87,-3.04 cw(c-8.87,-1.04) -10.87,-1.04 -10.87,51.96 4.63,51.96 ccw(c4.63,52.46) 4.63,52.96 -10.87,52.96 -10.87,75.46 cw(c-8.87,75.46) -8.87,77.46 57.13,77.46 cw(c57.13,75.46) 59.13,75.46 ; 37.63,-3.04 37.63,-3.04 ; 37.63,-3.04 57.13,-3.04 ccw(c57.13,-1.04) 59.13,-1.04 59.13,51.96 43.13,51.96 cw(c43.13,52.46) 43.13,52.96 59.13,52.96 59.13,75.46 ; 59.13,75.46 59.13,75.46 ; 8.13,51.96 cw(c8.13,52.46) 8.13,52.96 27.13,52.96 cw(c27.13,52.46) 27.13,51.96 8.13,51.96 ; 31.75,51.96 cw(c31.75,52.46) 31.75,52.96 39.08,52.96 cw(c39.08,52.46) 39.08,51.96 31.75,51.96
  lines w0.2: 76.918,59.925 168.51,59.925 ; 76.918,81.925 168.51,81.925 ; 85.898,57.175 85.898,84.675 ; 95.429,57.175 95.429,84.675 ; 113.565,57.175 113.565,84.675 ; 120.607,57.175 120.607,84.675 ; 131.175,57.175 131.175,84.675 ; 147.986,57.175 147.986,84.675 ; 76.918,57.175 168.51,57.175 168.51,84.675 76.918,84.675 76.918,57.175
  lines w0.25: 65,33 185,33 ; 65,41 185,41 ; 64,16.27 ccw(c65.27,16.27) 65.27,15 67,15 184.73,15 ccw(c184.73,16.27) 186,16.27 186,17 186,47.73 ccw(c184.73,47.73) 184.73,49 74,49 65.27,49 ccw(c65.27,47.73) 64,47.73 64,46 64,16.27
  lines w0.5: 76,-2.25 76,-2 ; 76,-1.25 76,3.75 ; 168,-2.25 168,-2 ; 168,-1.25 168,3.75 ; 72,-3.25 80,-3.25 76,5.75 72,-3.25 ; 164,-3.25 168,5.75 172,-3.25 164,-3.25
  text "Symbol" at 78.568,82.75 h1.32
  text "Count" at 86.723,82.75 h1.32
  text "Hole Size" at 96.254,82.75 h1.32
  text "Plated" at 114.39,82.75 h1.32
  text "Hole Type" at 121.432,82.75 h1.32
  text "Hole Length" at 132,82.75 h1.32
  text "Routed Path Length" at 148.811,82.75 h1.32
  text "2" at 86.723,80 h1.1
  text "0,600mm (23,62mil)" at 96.254,80 h1.1
  text "PTH" at 114.39,80 h1.1
  text "Slot" at 121.432,80 h1.1
  text "1,300mm (51,18mil)" at 132,80 h1.1
  text "0,700mm (27,56mil)" at 148.811,80 h1.1
  text "2" at 86.723,77.25 h1.1
  text "0,900mm (35,43mil)" at 96.254,77.25 h1.1
  text "PTH" at 114.39,77.25 h1.1
  text "Round" at 121.432,77.25 h1.1
  text "-" at 132,77.25 h1.1
  text "-" at 148.811,77.25 h1.1
  text "2" at 86.723,74.5 h1.1
  text "1,000mm (39,37mil)" at 96.254,74.5 h1.1
  text "NPTH" at 114.39,74.5 h1.1
  text "Round" at 121.432,74.5 h1.1
  text "-" at 132,74.5 h1.1
  text "-" at 148.811,74.5 h1.1
  text "3" at 86.723,71.75 h1.1
  text "3,200mm (125,98mil)" at 96.254,71.75 h1.1
  text "NPTH" at 114.39,71.75 h1.1
  text "Round" at 121.432,71.75 h1.1
  text "-" at 132,71.75 h1.1
  text "-" at 148.811,71.75 h1.1
  text "32" at 86.723,69 h1.1
  text "1,100mm (43,31mil)" at 96.254,69 h1.1
  text "PTH" at 114.39,69 h1.1
  text "Round" at 121.432,69 h1.1
  text "-" at 132,69 h1.1
  text "-" at 148.811,69 h1.1
  text "119" at 86.723,66.25 h1.1
  text "1,000mm (39,37mil)" at 96.254,66.25 h1.1
  text "PTH" at 114.39,66.25 h1.1
  text "Round" at 121.432,66.25 h1.1
  text "-" at 132,66.25 h1.1
  text "-" at 148.811,66.25 h1.1
  text "198" at 86.723,63.5 h1.1
  text "0,300mm (11,81mil)" at 96.254,63.5 h1.1
  text "PTH" at 114.39,63.5 h1.1
  text "Round" at 121.432,63.5 h1.1
  text "-" at 132,63.5 h1.1
  text "-" at 148.811,63.5 h1.1
  text "802" at 86.723,60.75 h1.1
  text "0,200mm (7,87mil)" at 96.254,60.75 h1.1
  text "PTH" at 114.39,60.75 h1.1
  text "Round" at 121.432,60.75 h1.1
  text "-" at 132,60.75 h1.1
  text "-" at 148.811,60.75 h1.1
  text "1160 Total" at 86.723,58 h1.1
  text "Slot definitions :" at 78.568,55.489 h1.1
  text "Routed Path Length" at 91.846,55.489 h1.1
  text "= Calculated from tool start centre position to tool end centre position." at 107.726,55.489 h1.1
  text "Hole Length" at 91.846,53.802 h1.1
  text "= Routed Path Length + Tool Size = Slot length as defined in the PCB layout" at 101.447,53.802 h1.1
  text "Layer Stack Up Detail for: MB1319C.PcbDoc" at 84,44 h3
  text "Layer" at 66,38 h1.5
  text "Gerber" at 92,38 h1.5
  text "Copper" at 109,38 h1.5
  text "Dielectric" at 125,38 h1.5
  text "Dielectric" at 141,38 h1.5
  text "Dielectric" at 160,38 h1.5
  text "Dielectric" at 175,38 h1.5
  text "Name" at 66,35 h1.5
  text "Document" at 92,35 h1.5
  text "Thickness" at 109,35 h1.5
  text "Height" at 125,35 h1.5
  text "Material" at 141,35 h1.5
  text "Constant" at 160,35 h1.5
  text "Type" at 175,35 h1.5
  text "Top Solder Mask" at 66,30 h1.5
  text "(.GTS)" at 92,30 h1.5
  text "0.4mil" at 125,30 h1.5
  text "Solder Resist" at 141,30 h1.5
  text "3.50" at 161,30 h1.5
  text "Top Layer" at 66,26 h1.5
  text "(.GTL)" at 92,26 h1.5
  text "1.4mil" at 110,26 h1.5
  text "59.055mil" at 125,24 h1.5
  text "FR-4" at 141,24 h1.5
  text "4.80" at 161,24 h1.5
  text "Core" at 176,24 h1.5
  text "Bottom Layer" at 66,22 h1.5
  text "(.GBL)" at 92,22 h1.5
  text "1.4mil" at 110,22 h1.5
  text "Bottom Solder Mask" at 66,18 h1.5
  text "(.GBS)" at 92,18 h1.5
  text "0.4mil" at 125,18 h1.5
  text "Solder Resist" at 141,18 h1.5
  text "3.50" at 161,18 h1.5
  text "Notes:" at 87.375,6.025 h2.5
  text "Silkscreen color : Blue ink PANTONE 2955" at 87.375,2.025 h2.5
  text "Solder resist color : White" at 87.375,-1.975 h2.5
  text "Plating type : lead Gold" at 87.375,-5.975 h2.5
  text "FAB DRAWING & DRILL LEGEND" at 4.05,-25.825 h1.9
Mechanical 27:
  lines w0.127: 37.63,-3.04 35.63,-5.04 2.63,-5.04 0.63,-3.04 -8.87,-3.04 cw(c-8.87,-1.04) -10.87,-1.04 -10.87,51.96 4.63,51.96 ccw(c4.63,52.46) 4.63,52.96 -10.87,52.96 -10.87,75.46 cw(c-8.87,75.46) -8.87,77.46 57.13,77.46 cw(c57.13,75.46) 59.13,75.46 ; 37.63,-3.04 37.63,-3.04 ; 37.63,-3.04 57.13,-3.04 ccw(c57.13,-1.04) 59.13,-1.04 59.13,51.96 43.13,51.96 cw(c43.13,52.46) 43.13,52.96 59.13,52.96 59.13,75.46 ; 59.13,75.46 59.13,75.46 ; 8.13,51.96 cw(c8.13,52.46) 8.13,52.96 27.13,52.96 cw(c27.13,52.46) 27.13,51.96 8.13,51.96 ; 31.75,51.96 cw(c31.75,52.46) 31.75,52.96 39.08,52.96 cw(c39.08,52.46) 39.08,51.96 31.75,51.96
  text "ASSEMBLY DRAWING, (PRIMARY)" at 3.65,-25.675 h1.9
Mechanical 30:
  lines w0.127: 37.63,-3.04 57.13,-3.04 ccw(c57.13,-1.04) 59.13,-1.04 59.13,51.96 43.13,51.96 cw(c43.13,52.46) 43.13,52.96 59.13,52.96 59.13,75.46 ; 37.63,-3.04 37.63,-3.04 ; 37.63,-3.04 35.63,-5.04 2.63,-5.04 0.63,-3.04 -8.87,-3.04 cw(c-8.87,-1.04) -10.87,-1.04 -10.87,51.96 4.63,51.96 ccw(c4.63,52.46) 4.63,52.96 -10.87,52.96 -10.87,75.46 cw(c-8.87,75.46) -8.87,77.46 57.13,77.46 cw(c57.13,75.46) 59.13,75.46 ; 59.13,75.46 59.13,75.46 ; 8.13,51.96 cw(c8.13,52.46) 8.13,52.96 27.13,52.96 cw(c27.13,52.46) 27.13,51.96 8.13,51.96 ; 31.75,51.96 cw(c31.75,52.46) 31.75,52.96 39.08,52.96 cw(c39.08,52.46) 39.08,51.96 31.75,51.96
  text "ASSEMBLY DRAWING, (SECONDARY)" at 47.8,-25.475 h1.7

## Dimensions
-8.87,77.46 to 2.63,-5.04 on Drill Drawing
-10.87,75.46 to 59.13,75.46 on Drill Drawing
